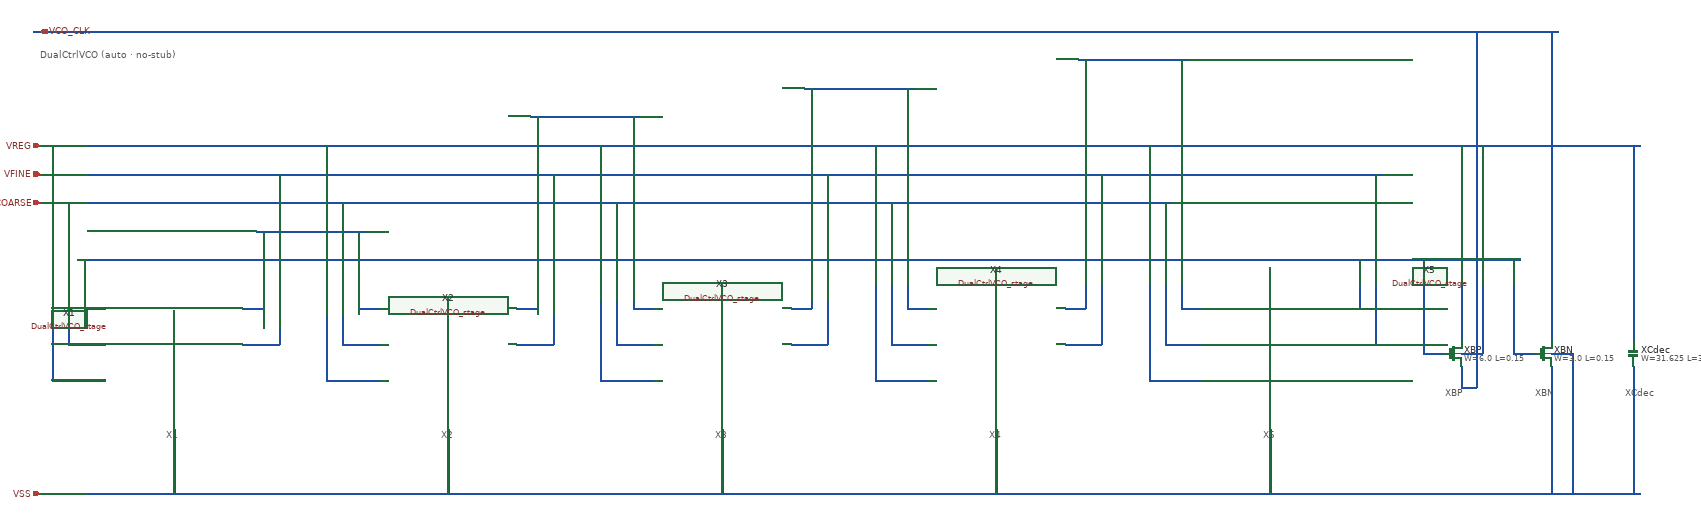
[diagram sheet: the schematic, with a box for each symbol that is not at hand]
v {xschem version=3.4.6 file_version=1.2}
G {}
K {}
V {}
S {}
E {}
T {DualCtrlVCO   (auto · no-stub)} -300 -680 0 0 0.4 0.4 {layer=4}
C {DualCtrlVCO_stage.sym} 0 0 0 0 {name=X1}
N -154 -100 -200 -100 {}
N 154 -100 200 -100 {}
N -154 -20 -236 -20 {}
N 154 -20 236 -20 {}
N -154 60 -272 60 {}
N 0 170 0 216 {}
T {X1} -16 170 0 0 0.11 0.11 {layer=13}
C {DualCtrlVCO_stage.sym} 614 0 0 0 {name=X2}
N 460 -100 414 -100 {}
N 768 -100 814 -100 {}
N 460 -20 378 -20 {}
N 768 -20 850 -20 {}
N 460 60 342 60 {}
N 614 170 614 216 {}
T {X2} 598 170 0 0 0.11 0.11 {layer=13}
C {DualCtrlVCO_stage.sym} 1228 0 0 0 {name=X3}
N 1074 -100 1028 -100 {}
N 1382 -100 1428 -100 {}
N 1074 -20 992 -20 {}
N 1382 -20 1464 -20 {}
N 1074 60 956 60 {}
N 1228 170 1228 216 {}
T {X3} 1212 170 0 0 0.11 0.11 {layer=13}
C {DualCtrlVCO_stage.sym} 1842 0 0 0 {name=X4}
N 1688 -100 1642 -100 {}
N 1996 -100 2042 -100 {}
N 1688 -20 1606 -20 {}
N 1996 -20 2078 -20 {}
N 1688 60 1570 60 {}
N 1842 170 1842 216 {}
T {X4} 1826 170 0 0 0.11 0.11 {layer=13}
C {DualCtrlVCO_stage.sym} 2456 0 0 0 {name=X5}
N 2302 -100 2256 -100 {}
N 2610 -100 2656 -100 {}
N 2302 -20 2220 -20 {}
N 2610 -20 2692 -20 {}
N 2302 60 2184 60 {}
N 2456 170 2456 216 {}
T {X5} 2440 170 0 0 0.11 0.11 {layer=13}
C {sky130_fd_pr/pfet_01v8.sym} 2864 0 0 0 {name=XBP
L=0.15
W=6.0
nf=1
model=pfet_01v8
spiceprefix=X}
N 2884 30 2884 76 {}
N 2844 0 2798 0 {}
N 2884 -30 2884 -76 {}
N 2884 0 2930 0 {}
T {XBP} 2848 76 0 0 0.11 0.11 {layer=13}
C {sky130_fd_pr/nfet_01v8.sym} 3066 0 0 0 {name=XBN
L=0.15
W=3.0
nf=1
model=nfet_01v8
spiceprefix=X}
N 3086 -30 3086 -76 {}
N 3046 0 3000 0 {}
N 3086 30 3086 76 {}
N 3086 0 3132 0 {}
T {XBN} 3050 76 0 0 0.11 0.11 {layer=13}
C {sky130_fd_pr/cap_mim_m3_1.sym} 3268 0 0 0 {name=XCdec
model=cap_mim_m3_1
W=31.625
L=31.625
MF=1
spiceprefix=X}
N 3268 -30 3268 -76 {}
N 3268 30 3268 76 {}
T {XCdec} 3252 76 0 0 0.11 0.11 {layer=13}
N -200 -100 -200 -210 {}
N 2656 -100 2656 -210 {}
N 2798 0 2798 -210 {}
N 3000 0 3000 -210 {}
N 200 -100 200 -274 {}
N 414 -100 414 -274 {}
N -236 -20 -236 -338 {}
N 378 -20 378 -338 {}
N 992 -20 992 -338 {}
N 1606 -20 1606 -338 {}
N 2220 -20 2220 -338 {}
N 236 -20 236 -402 {}
N 850 -20 850 -402 {}
N 1464 -20 1464 -402 {}
N 2078 -20 2078 -402 {}
N 2692 -20 2692 -402 {}
N -272 60 -272 -466 {}
N 342 60 342 -466 {}
N 956 60 956 -466 {}
N 1570 60 1570 -466 {}
N 2184 60 2184 -466 {}
N 2884 -76 2884 -466 {}
N 2930 0 2930 -466 {}
N 3268 -76 3268 -466 {}
N 0 216 0 314 {}
N 614 216 614 314 {}
N 1228 216 1228 314 {}
N 1842 216 1842 314 {}
N 2456 216 2456 314 {}
N 3086 76 3086 314 {}
N 3132 0 3132 314 {}
N 3268 76 3268 314 {}
N 814 -100 814 -530 {}
N 1028 -100 1028 -530 {}
N 1428 -100 1428 -594 {}
N 1642 -100 1642 -594 {}
N 2042 -100 2042 -658 {}
N 2256 -100 2256 -658 {}
N 3086 -76 3086 -722 {}
N 2884 76 2918 76 {}
N 2918 76 2918 -722 {}
C {devices/ipin.sym} -300 314 0 0 {name=ip1 lab=VSS}
C {devices/ipin.sym} -300 -466 0 0 {name=ip2 lab=VREG}
C {devices/ipin.sym} -300 -338 0 0 {name=ip3 lab=VCOARSE}
C {devices/ipin.sym} -300 -402 0 0 {name=ip4 lab=VFINE}
C {devices/opin.sym} -300 -722 0 0 {name=op5 lab=VCO_CLK}
N -216 -210 3016 -210 {}
N 184 -274 430 -274 {}
N -316 -338 2236 -338 {}
N -316 -402 2708 -402 {}
N -316 -466 3284 -466 {}
N -316 314 3284 314 {lab=VSS}
N 798 -530 1044 -530 {}
N 1412 -594 1658 -594 {}
N 2026 -658 2272 -658 {}
N -316 -722 3102 -722 {}
